VERSION 5.8 ;
BUSBITCHARS "[]" ;
DIVIDERCHAR "/" ;
UNITS
    DATABASE MICRONS 1000 ;
END UNITS

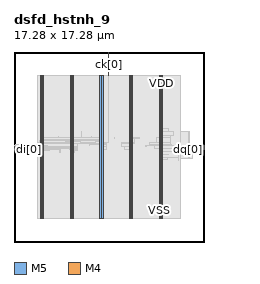
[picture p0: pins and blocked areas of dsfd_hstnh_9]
MACRO dsfd_hstnh_9
  FOREIGN dsfd_hstnh_9 0 0 ;
  CLASS BLOCK ;
  SIZE 17.28 BY 17.28 ;
  PIN ck[0]
    DIRECTION INPUT ;
    USE SIGNAL ;
    PORT
      LAYER M5 ;
        RECT  8.592 17.196 8.616 17.28 ;
    END
    PORT
      LAYER M5 ;
        RECT  8.592 15.143 8.616 17.232 ;
    END
  END ck[0]
  PIN di[0]
    DIRECTION INPUT ;
    USE SIGNAL ;
    PORT
      LAYER M4 ;
        RECT  0 8.4 0.084 8.424 ;
    END
  END di[0]
  PIN di[1]
    DIRECTION INPUT ;
    USE SIGNAL ;
    PORT
      LAYER M4 ;
        RECT  0 8.448 0.084 8.472 ;
    END
  END di[1]
  PIN di[2]
    DIRECTION INPUT ;
    USE SIGNAL ;
    PORT
      LAYER M4 ;
        RECT  0 8.496 0.084 8.52 ;
    END
  END di[2]
  PIN di[3]
    DIRECTION INPUT ;
    USE SIGNAL ;
    PORT
      LAYER M4 ;
        RECT  0 8.544 0.084 8.568 ;
    END
  END di[3]
  PIN di[4]
    DIRECTION INPUT ;
    USE SIGNAL ;
    PORT
      LAYER M4 ;
        RECT  0 8.592 0.084 8.616 ;
    END
  END di[4]
  PIN di[5]
    DIRECTION INPUT ;
    USE SIGNAL ;
    PORT
      LAYER M4 ;
        RECT  0 8.64 0.084 8.664 ;
    END
  END di[5]
  PIN di[6]
    DIRECTION INPUT ;
    USE SIGNAL ;
    PORT
      LAYER M4 ;
        RECT  0 8.688 0.084 8.712 ;
    END
  END di[6]
  PIN di[7]
    DIRECTION INPUT ;
    USE SIGNAL ;
    PORT
      LAYER M4 ;
        RECT  0 8.736 0.084 8.76 ;
    END
  END di[7]
  PIN di[8]
    DIRECTION INPUT ;
    USE SIGNAL ;
    PORT
      LAYER M4 ;
        RECT  0 8.784 0.084 8.808 ;
    END
  END di[8]
  PIN dq[0]
    DIRECTION OUTPUT ;
    USE SIGNAL ;
    PORT
      LAYER M4 ;
        RECT  17.196 8.4 17.28 8.424 ;
    END
  END dq[0]
  PIN dq[1]
    DIRECTION OUTPUT ;
    USE SIGNAL ;
    PORT
      LAYER M4 ;
        RECT  17.196 8.448 17.28 8.472 ;
    END
  END dq[1]
  PIN dq[2]
    DIRECTION OUTPUT ;
    USE SIGNAL ;
    PORT
      LAYER M4 ;
        RECT  17.196 8.496 17.28 8.52 ;
    END
  END dq[2]
  PIN dq[3]
    DIRECTION OUTPUT ;
    USE SIGNAL ;
    PORT
      LAYER M4 ;
        RECT  17.196 8.544 17.28 8.568 ;
    END
  END dq[3]
  PIN dq[4]
    DIRECTION OUTPUT ;
    USE SIGNAL ;
    PORT
      LAYER M4 ;
        RECT  17.196 8.592 17.28 8.616 ;
    END
  END dq[4]
  PIN dq[5]
    DIRECTION OUTPUT ;
    USE SIGNAL ;
    PORT
      LAYER M4 ;
        RECT  17.196 8.64 17.28 8.664 ;
    END
  END dq[5]
  PIN dq[6]
    DIRECTION OUTPUT ;
    USE SIGNAL ;
    PORT
      LAYER M4 ;
        RECT  17.196 8.688 17.28 8.712 ;
    END
  END dq[6]
  PIN dq[7]
    DIRECTION OUTPUT ;
    USE SIGNAL ;
    PORT
      LAYER M4 ;
        RECT  17.196 8.736 17.28 8.76 ;
    END
  END dq[7]
  PIN dq[8]
    DIRECTION OUTPUT ;
    USE SIGNAL ;
    PORT
      LAYER M4 ;
        RECT  17.196 8.784 17.28 8.808 ;
    END
  END dq[8]
  PIN VDD
    DIRECTION INOUT ;
    USE POWER ;
    PORT
      LAYER M5 ;
        RECT  13.392 2.151 13.512 15.129 ;
        RECT  10.692 2.151 10.812 15.129 ;
        RECT  7.992 2.151 8.112 15.129 ;
        RECT  5.292 2.151 5.412 15.129 ;
        RECT  2.592 2.151 2.712 15.129 ;
    END
  END VDD
  PIN VSS
    DIRECTION INOUT ;
    USE GROUND ;
    PORT
      LAYER M5 ;
        RECT  13.2 2.137 13.32 15.143 ;
        RECT  10.5 2.137 10.62 15.143 ;
        RECT  7.8 2.137 7.92 15.143 ;
        RECT  5.1 2.137 5.22 15.143 ;
        RECT  2.4 2.137 2.52 15.143 ;
    END
  END VSS
  # OT_OBS_CLOSED layer=M5 d_um=1.536 added=0
  OBS
    LAYER RVTN ;
     RECT  2.16 2.16 15.12 2.295 ;
     RECT  2.16 2.565 15.12 2.835 ;
     RECT  2.16 3.105 15.12 3.375 ;
     RECT  2.16 3.645 15.12 3.915 ;
     RECT  2.16 4.185 15.12 4.455 ;
     RECT  2.16 4.725 15.12 4.995 ;
     RECT  2.16 5.265 15.12 5.535 ;
     RECT  2.16 5.805 15.12 6.075 ;
     RECT  2.16 6.345 15.12 6.615 ;
     RECT  2.16 6.885 15.12 7.155 ;
     RECT  2.16 7.425 15.12 7.695 ;
     RECT  2.16 7.965 15.12 8.235 ;
     RECT  2.16 8.505 15.12 8.775 ;
     RECT  2.16 9.045 15.12 9.315 ;
     RECT  2.16 9.585 15.12 9.855 ;
     RECT  2.16 10.125 15.12 10.395 ;
     RECT  2.16 10.665 15.12 10.935 ;
     RECT  2.16 11.205 15.12 11.475 ;
     RECT  2.16 11.745 15.12 12.015 ;
     RECT  2.16 12.285 15.12 12.555 ;
     RECT  2.16 12.825 15.12 13.095 ;
     RECT  2.16 13.365 15.12 13.635 ;
     RECT  2.16 13.905 15.12 14.175 ;
     RECT  2.16 14.445 15.12 14.715 ;
     RECT  2.16 14.985 15.12 15.12 ;
    LAYER RVTP ;
     RECT  2.16 2.295 15.12 2.565 ;
     RECT  2.16 2.835 15.12 3.105 ;
     RECT  2.16 3.375 15.12 3.645 ;
     RECT  2.16 3.915 15.12 4.185 ;
     RECT  2.16 4.455 15.12 4.725 ;
     RECT  2.16 4.995 15.12 5.265 ;
     RECT  2.16 5.535 15.12 5.805 ;
     RECT  2.16 6.075 15.12 6.345 ;
     RECT  2.16 6.615 15.12 6.885 ;
     RECT  2.16 7.155 15.12 7.425 ;
     RECT  2.16 7.695 15.12 7.965 ;
     RECT  2.16 8.235 15.12 8.505 ;
     RECT  2.16 8.775 15.12 9.045 ;
     RECT  2.16 9.315 15.12 9.585 ;
     RECT  2.16 9.855 15.12 10.125 ;
     RECT  2.16 10.395 15.12 10.665 ;
     RECT  2.16 10.935 15.12 11.205 ;
     RECT  2.16 11.475 15.12 11.745 ;
     RECT  2.16 12.015 15.12 12.285 ;
     RECT  2.16 12.555 15.12 12.825 ;
     RECT  2.16 13.095 15.12 13.365 ;
     RECT  2.16 13.635 15.12 13.905 ;
     RECT  2.16 14.175 15.12 14.445 ;
     RECT  2.16 14.715 15.12 14.985 ;
    LAYER M1 ;
     RECT  2.16 2.151 15.12 15.129 ;
    LAYER M2 ;
     RECT  0.139 8.442 2.16 8.46 ;
     RECT  2.16 2.151 15.12 15.129 ;
     RECT  15.12 7.596 15.863 10.044 ;
     RECT  15.863 7.596 15.899 8.694 ;
     RECT  15.863 9.756 15.935 10.044 ;
     RECT  15.899 7.596 15.971 8.424 ;
     RECT  15.935 10.026 15.971 10.044 ;
     RECT  15.971 7.596 16.259 8.154 ;
     RECT  16.259 8.136 16.547 8.154 ;
    LAYER M3 ;
     RECT  2.415 2.143 2.505 2.413 ;
     RECT  5.115 2.143 5.205 2.413 ;
     RECT  7.815 2.143 7.905 2.413 ;
     RECT  10.515 2.143 10.605 2.413 ;
     RECT  13.215 2.143 13.305 2.413 ;
     RECT  13.215 2.413 13.497 7.501 ;
     RECT  13.215 7.501 13.986 7.663 ;
     RECT  14.976 7.393 14.994 7.663 ;
     RECT  5.115 2.413 5.397 8.131 ;
     RECT  16.236 7.591 16.254 8.131 ;
     RECT  13.215 7.663 14.994 8.203 ;
     RECT  2.415 2.413 2.697 8.275 ;
     RECT  2.304 8.275 2.697 8.311 ;
     RECT  5.115 8.131 5.49 8.311 ;
     RECT  16.236 8.131 16.542 8.392 ;
     RECT  2.304 8.311 3.258 8.401 ;
     RECT  4.176 8.167 4.194 8.401 ;
     RECT  5.115 8.311 5.742 8.401 ;
     RECT  10.515 2.413 10.797 8.401 ;
     RECT  7.815 2.413 8.097 8.437 ;
     RECT  15.948 8.392 16.542 8.443 ;
     RECT  2.304 8.401 4.194 8.509 ;
     RECT  5.004 8.401 5.742 8.509 ;
     RECT  13.212 8.203 14.994 8.509 ;
     RECT  0.144 8.437 0.162 8.573 ;
     RECT  2.304 8.509 5.742 8.581 ;
     RECT  15.876 8.443 16.542 8.635 ;
     RECT  7.815 8.437 8.37 8.671 ;
     RECT  10.08 8.401 10.797 8.671 ;
     RECT  2.304 8.581 5.814 8.683 ;
     RECT  15.84 8.635 16.542 8.717 ;
     RECT  0.324 8.635 0.342 8.765 ;
     RECT  11.988 8.707 12.006 8.779 ;
     RECT  12.816 8.509 14.994 8.779 ;
     RECT  11.988 8.779 14.994 8.807 ;
     RECT  12.312 8.807 14.994 8.813 ;
     RECT  6.84 8.743 6.858 8.851 ;
     RECT  7.776 8.671 8.37 8.851 ;
     RECT  12.312 8.813 14.31 8.879 ;
     RECT  2.268 8.683 5.814 8.923 ;
     RECT  6.84 8.851 8.37 8.923 ;
     RECT  9.792 8.671 10.797 8.941 ;
     RECT  2.268 8.923 8.37 9.005 ;
     RECT  9.792 8.941 10.926 9.005 ;
     RECT  12.312 8.879 14.202 9.077 ;
     RECT  15.84 8.717 15.966 9.239 ;
     RECT  2.304 9.005 8.37 9.275 ;
     RECT  2.415 9.275 8.37 9.311 ;
     RECT  10.515 9.005 10.926 9.391 ;
     RECT  2.415 9.311 8.097 9.509 ;
     RECT  10.515 9.391 11.43 9.509 ;
     RECT  2.415 9.509 3.078 9.545 ;
     RECT  4.032 9.509 8.097 9.545 ;
     RECT  9.144 9.391 9.162 9.545 ;
     RECT  12.96 9.077 14.202 9.545 ;
     RECT  4.032 9.545 4.05 9.617 ;
     RECT  7.056 9.545 7.074 9.617 ;
     RECT  13.215 9.545 14.202 9.661 ;
     RECT  15.912 9.239 15.966 9.779 ;
     RECT  6.12 9.545 6.138 10.049 ;
     RECT  15.948 9.779 15.966 10.049 ;
     RECT  13.215 9.661 14.526 10.085 ;
     RECT  13.215 10.085 14.058 10.319 ;
     RECT  13.215 10.319 13.698 10.355 ;
     RECT  2.415 9.545 2.697 14.867 ;
     RECT  5.115 9.545 5.397 14.867 ;
     RECT  7.815 9.545 8.097 14.867 ;
     RECT  10.515 9.509 10.797 14.867 ;
     RECT  13.215 10.355 13.497 14.867 ;
     RECT  2.415 14.867 2.505 15.137 ;
     RECT  5.115 14.867 5.205 15.137 ;
     RECT  7.815 14.867 7.905 15.137 ;
     RECT  10.515 14.867 10.605 15.137 ;
     RECT  13.215 14.867 13.305 15.137 ;
    LAYER M4 ;
     RECT  0.06 8.4 0.133 8.808 ;
     RECT  0.133 8.4 2.408 8.856 ;
     RECT  2.408 2.148 2.512 15.132 ;
     RECT  2.512 2.418 2.704 14.862 ;
     RECT  2.704 8.736 3.089 8.76 ;
     RECT  4.705 9.072 5.108 9.096 ;
     RECT  5.108 2.148 5.212 15.132 ;
     RECT  5.212 2.418 5.404 14.862 ;
     RECT  5.404 8.928 6.005 9.096 ;
     RECT  6.005 8.928 7.369 9.048 ;
     RECT  7.369 8.928 7.808 9.144 ;
     RECT  7.808 2.148 7.912 15.132 ;
     RECT  7.912 2.418 8.104 14.862 ;
     RECT  8.104 9.024 8.381 9.144 ;
     RECT  8.381 9.024 8.627 9.048 ;
     RECT  10.508 2.148 10.612 15.132 ;
     RECT  10.612 2.418 10.804 14.862 ;
     RECT  13.208 2.148 13.312 15.132 ;
     RECT  13.312 2.418 13.504 14.862 ;
     RECT  13.504 7.968 14.069 7.992 ;
     RECT  14.821 8.544 14.965 8.568 ;
     RECT  14.965 8.544 15.865 8.808 ;
     RECT  15.865 8.448 15.937 8.808 ;
     RECT  15.937 8.4 17.244 8.808 ;
    LAYER M5 ;
     RECT  2.4 2.137 2.52 2.151 ;
     RECT  5.1 2.137 5.22 2.151 ;
     RECT  7.8 2.137 7.92 2.151 ;
     RECT  10.5 2.137 10.62 2.151 ;
     RECT  13.2 2.137 13.32 2.151 ;
     RECT  0.144 8.725 0.168 8.867 ;
     RECT  7.8 2.151 8.112 9.013 ;
     RECT  2.4 2.151 2.712 15.129 ;
     RECT  5.1 2.151 5.412 15.129 ;
     RECT  10.5 2.151 10.812 15.129 ;
     RECT  13.2 2.151 13.512 15.129 ;
     RECT  2.4 15.129 2.52 15.143 ;
     RECT  5.1 15.129 5.22 15.143 ;
     RECT  7.8 9.013 8.616 15.143 ;
     RECT  10.5 15.129 10.62 15.143 ;
     RECT  13.2 15.129 13.32 15.143 ;
  END
END dsfd_hstnh_9
END LIBRARY
